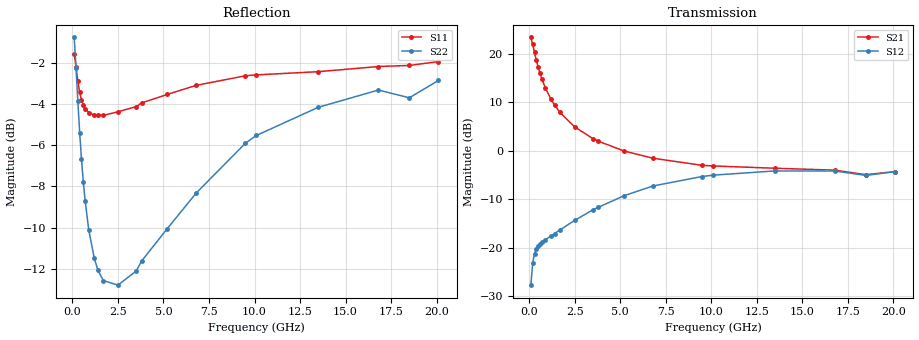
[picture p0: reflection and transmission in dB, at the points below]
!  Infineon Technologies AG
! BFR380L3 , PF131585-7, No.6, Th 09.10.01, soldered on pcb-board, measured with PP GSG850
!  Vce=0.5 V,  Ic=5.0 mA
! Common Emitter S-Parameters:  15. November 2001
#  GHz  S  MA  R  50
! f  S11  S21  S12  S22
! GHz  Mag  Ang  Mag  Ang  Mag  Ang  Mag  Ang
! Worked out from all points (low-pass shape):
!   201 points, 100 MHz to 20.1 GHz, reference 50 ohm
!   highest |S21| = 23.36 dB at 100 MHz (marker M1); lowest = -4.9 dB at 18.5 GHz (marker M2)
!   |S21| within 3 dB of the highest: start of sweep to 293.6 MHz
!   lowest |S11| = -4.5 dB at 1.7 GHz (marker M3), VSWR 3.91, Z = 12.8 + j0.902 ohm
!   |S11| at or under -10 dB: nowhere
!   |S22| runs from -12.8 to -0.8 dB; largest |S21 - S12| = 15
!   S11 on the Smith chart (normalised r, x): 100 MHz: 0.85, -2.82; 300 MHz: 0.32, -0.94; 900 MHz: 0.26, -0.22; 3.8 GHz: 0.25, +0.35; 9.5 GHz: 0.35, +1.12; 20.1 GHz: 0.93, +2.57
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0.1  0.8365 -36.3  14.72 156.9  0.04138 69.6  0.916 -26.0
0.2  0.7781 -67.5  12.44 138.5  0.07046 56.2  0.774 -46.5
0.3  0.7173 -90.7  10.29 125.4  0.08728 47.2  0.6411 -61.5
0.4  0.6732 -108.3  8.582 115.8  0.09728 41.8  0.5381 -72.6
0.5  0.6454 -121.7  7.281 108.6  0.104 38.9  0.4636 -81.4
0.6  0.6276 -132.1  6.281 103.0  0.1093 37.4  0.4087 -88.6
0.7  0.6152 -140.5  5.522 98.2  0.1139 36.5  0.3678 -94.9
0.9  0.6016 -153.3  4.419 90.7  0.1215 36.4  0.3121 -105.0
1.2  0.5934 -166.8  3.407 82.0  0.1329 37.6  0.2669 -116.9
1.4  0.5932 -173.7  2.962 77.1  0.1407 38.8  0.2493 -123.5
1.7  0.5924 177.8  2.481 70.6  0.1534 40.5  0.2353 -131.8
2.5  0.6043 160.2  1.765 56.0  0.1917 43.4  0.2294 -148.3
3.5  0.6219 143.1  1.337 41.1  0.2466 43.8  0.2481 -163.6
3.8  0.635 138.9  1.257 37.5  0.2617 43.2  0.2624 -168.3
5.2  0.6658 120.6  0.9978 21.9  0.3437 37.6  0.3142 174.7
6.8  0.7006 102.7  0.8387 9.2  0.434 29.1  0.3838 154.3
9.5  0.7391 80.6  0.7089 -5.2  0.5436 12.1  0.507 127.5
10.1  0.7428 76.6  0.6983 -7.6  0.5611 8.3  0.5294 121.7
13.5  0.7562 59.1  0.6612 -21.4  0.6203 -12.0  0.6197 94.2
16.8  0.7783 47.4  0.632 -32.4  0.6189 -27.2  0.6825 74.2
18.5  0.7831 45.5  0.5669 -39.4  0.558 -35.2  0.6535 69.2
20.1  0.8001 38.5  0.612 -43.2  0.6095 -40.0  0.7201 58.9
